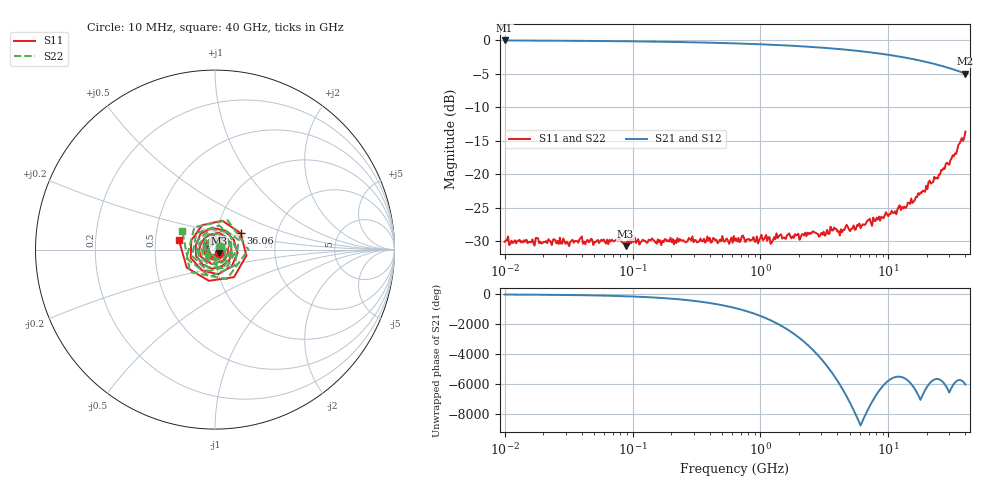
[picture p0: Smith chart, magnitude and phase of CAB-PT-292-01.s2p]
! CAL-ELEKTRA — DATOS SINTÉTICOS DE EJEMPLO: no son una medida real.
! Cable simulado CAB-PT-292-01: 1.0 m, 10 MHz – 40 GHz
# HZ S RI R 50
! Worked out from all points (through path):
!   401 points, 10 MHz to 40 GHz, reference 50 ohm
!   highest |S21| = -0.06 dB at 10 MHz (marker M1); lowest = -5.0 dB at 40 GHz (marker M2)
!   lowest |S11| = -30.7 dB at 88.21 MHz (marker M3), VSWR 1.06, Z = 52.1 - j2.16 ohm
!   |S11| at or under -10 dB: start of sweep to end of sweep
!   |S22| runs from -30.7 to -13.6 dB; largest |S21 - S12| = 0
!   S11 on the Smith chart (normalised r, x): 10 MHz: 1.05, -0.04; 36.06 GHz: 1.31, +0.25; 40 GHz: 0.66, +0.07
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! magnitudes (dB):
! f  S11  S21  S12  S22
! 10 MHz  -30.1  -0.1  -0.1  -30.1
! 31.28 MHz  -30.3  -0.1  -0.1  -30.3
! 40.12 MHz  -29.3  -0.1  -0.1  -29.3
! 77.9 MHz  -29.7  -0.2  -0.2  -29.7
! 88.21 MHz  -30.7  -0.2  -0.2  -30.7
! 160.9 MHz  -30.1  -0.2  -0.2  -30.1
! 645.7 MHz  -29.6  -0.5  -0.5  -29.6
! 937.8 MHz  -29.2  -0.6  -0.6  -29.2
! 1.13 GHz  -29.9  -0.7  -0.7  -29.9
! 1.254 GHz  -29.8  -0.7  -0.7  -29.8
! 1.391 GHz  -29.2  -0.7  -0.7  -29.2
! 2.105 GHz  -28.9  -0.9  -0.9  -28.9
! 2.537 GHz  -28.6  -1.0  -1.0  -28.6
! 2.934 GHz  -29.1  -1.1  -1.1  -29.1
! 3.685 GHz  -28.4  -1.3  -1.3  -28.4
! 4.173 GHz  -29.1  -1.4  -1.4  -29.1
! 10.18 GHz  -25.9  -2.2  -2.2  -25.9
! 13.33 GHz  -24.8  -2.6  -2.6  -24.8
! 19.36 GHz  -22.6  -3.2  -3.2  -22.6
! 31.19 GHz  -17.6  -4.3  -4.3  -17.6
! 36.06 GHz  -15.4  -4.7  -4.7  -15.4
! 40 GHz  -13.6  -5.0  -5.0  -13.6
